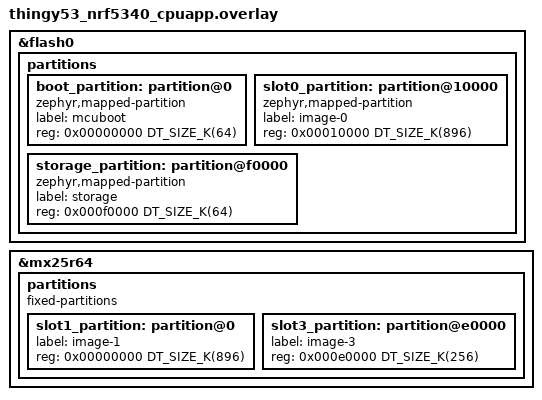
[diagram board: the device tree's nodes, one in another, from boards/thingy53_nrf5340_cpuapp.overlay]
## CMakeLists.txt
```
#
# Copyright (c) 2024 Nordic Semiconductor ASA
#
# SPDX-License-Identifier: LicenseRef-Nordic-5-Clause
#

cmake_minimum_required(VERSION 3.20.0)

find_package(Zephyr REQUIRED HINTS $ENV{ZEPHYR_BASE})
project(nrf_wifi_thread_coex)

target_sources(app PRIVATE
  src/ot_utils.c
  src/zperf_utils.c
  src/ot_coex_functions.c
  src/main.c
)

# For net_private.h
target_include_directories(app PUBLIC
  ${ZEPHYR_BASE}/subsys/net/ip
  ${ZEPHYR_BASE}/drivers/wifi/nrf_wifi/inc/
)
```

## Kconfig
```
#
# Copyright (c) 2024 Nordic Semiconductor
#
# SPDX-License-Identifier: LicenseRef-Nordic-5-Clause
#

source "Kconfig.zephyr"

menu "WiFi and Thread Coex sample"

config NET_CONFIG_PEER_IPV4_ADDR
	string "Peer IPv4 address"
	default "192.168.1.253"

config NET_CONFIG_PEER_IPV4_PORT
	int "Peer IPv4 port"
	default 5001

config WIFI_THREAD_STACK_SIZE
	int "Wi-Fi thread stack size"
	default 4096

config WIFI_THREAD_PRIORITY
	int "Wi-Fi thread priority"
	default 5

config WIFI_ZPERF_SERVER
	bool "Zperf role: server or client"

config WIFI_ZPERF_PROT_UDP
	bool "UDP or TCP"
	default y

config WIFI_ZPERF_PKT_SIZE
	int "packet size"
	default 1024

config WIFI_ZPERF_RATE
	int "rate in kbps"
	default 10000

# Thread configurations
config OT_CHANNEL
	int "Thread device operating channel"
	default 18

config OT_PAN_ID
	int "Thread device PAN ID"
	default 1

config OT_ROLE_CLIENT
	bool "Thread device role"
	default y

config OT_PACKET_SIZE
	int "Thread device packet size"
	default 256

config OT_RATE_BPS
	int "Thread device rate in bits per seconds"
	default 10000

config NET_CONFIG_THREAD_PORT
	int "Port for Thread zperf"
	default 5001

config OT_ZPERF_PROT_UDP
	bool "UDP or TCP"
	default y

# Test parameters
choice TEST_TYPE
	prompt "Test type"
	default TEST_TYPE_WLAN_OT

config TEST_TYPE_WLAN_ONLY
	bool "WLAN only"
	help
	  Enable WLAN only

config TEST_TYPE_OT_ONLY
	bool "Thread only"
	help
	  Enable Thread only

config TEST_TYPE_WLAN_OT
	bool "WLAN and Thread"
	help
	  Enable WLAN and Thread
endchoice

config TEST_TYPE_WLAN
	bool "WLAN"
	default y if TEST_TYPE_WLAN_ONLY || TEST_TYPE_WLAN_OT
	select WIFI
	help
	  Enable WLAN

config TEST_TYPE_OT
	bool "Thread"
	default y if TEST_TYPE_OT_ONLY || TEST_TYPE_WLAN_OT
	help
	  Enable Thread

config COEX_TEST_DURATION
	int "test duration in milliseconds"
	default 20000

config COEX_SEP_ANTENNAS
	bool "No support for shared antenna in Thread and WLAN. Set it to yes"
	default y

config SR_PROTOCOL_BLE
	bool "Indicates if the SR protocol is Bluetooth LE or not"

endmenu
```

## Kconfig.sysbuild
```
#
# Copyright (c) 2024 Nordic Semiconductor
#
# SPDX-License-Identifier: LicenseRef-Nordic-5-Clause
#

source "share/sysbuild/Kconfig"

config NRF_DEFAULT_IPC_RADIO
	depends on SOC_SERIES_NRF53 || SOC_SERIES_NRF54H
	default y
```

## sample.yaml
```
sample:
  description: Wi-Fi Thread coex sample application
  name: Wi-Fi Thread coex
tests:
  sample.nrf7002.thread_coex_sep_ant:
    sysbuild: true
    build_only: true
    integration_platforms:
      - nrf7002dk/nrf5340/cpuapp
    extra_args:
      - CONFIG_MPSL_CX=y
      - ipc_radio_CONFIG_MPSL_CX=y
      - CONFIG_COEX_SEP_ANTENNAS=y
      - EXTRA_CONF_FILE="overlay-wifi-udp-client-thread-udp-client.conf"
    platform_allow: nrf7002dk/nrf5340/cpuapp
    tags:
      - ci_build
      - sysbuild
      - ci_samples_wifi
  sample.nrf7001.thread_coex:
    sysbuild: true
    build_only: true
    integration_platforms:
      - nrf7002dk/nrf5340/cpuapp/nrf7001
    extra_args:
      - CONFIG_MPSL_CX=y
      - ipc_radio_CONFIG_MPSL_CX=y
      - CONFIG_COEX_SEP_ANTENNAS=y
      - EXTRA_CONF_FILE="overlay-wifi-udp-client-thread-udp-client.conf"
    platform_allow: nrf7002dk/nrf5340/cpuapp/nrf7001
    tags:
      - ci_build
      - sysbuild
      - ci_samples_wifi
  sample.nrf7002ek.thread_coex:
    sysbuild: true
    build_only: true
    integration_platforms:
      - nrf5340dk/nrf5340/cpuapp
    extra_args:
      - thread_coex_SHIELD="nrf7002ek;nrf7002ek_coex"
      - ipc_radio_SHIELD="nrf7002ek_coex"
      - CONFIG_MPSL_CX=y
      - ipc_radio_CONFIG_MPSL_CX=y
      - CONFIG_COEX_SEP_ANTENNAS=y
      - EXTRA_CONF_FILE="overlay-wifi-udp-client-thread-udp-client.conf"
    platform_allow: nrf5340dk/nrf5340/cpuapp
    tags:
      - ci_build
      - sysbuild
      - ci_samples_wifi
  sample.nrf7001ek.thread_coex:
    sysbuild: true
    build_only: true
    integration_platforms:
      - nrf5340dk/nrf5340/cpuapp
    extra_args:
      - thread_coex_SHIELD="nrf7002ek_nrf7001;nrf7002ek_coex"
      - ipc_radio_SHIELD="nrf7002ek_coex"
      - CONFIG_MPSL_CX=y
      - ipc_radio_CONFIG_MPSL_CX=y
      - CONFIG_COEX_SEP_ANTENNAS=y
      - EXTRA_CONF_FILE="overlay-wifi-udp-client-thread-udp-client.conf"
    platform_allow: nrf5340dk/nrf5340/cpuapp
    tags:
      - ci_build
      - sysbuild
      - ci_samples_wifi
  sample.nrf7002_eb.thingy53.thread_coex:
    sysbuild: true
    build_only: true
    extra_args:
      - thread_coex_SHIELD=nrf7002eb
      - ipc_radio_SHIELD=nrf7002eb_coex
      - CONFIG_MPSL_CX=y
      - ipc_radio_CONFIG_MPSL_CX=y
      - CONFIG_COEX_SEP_ANTENNAS=y
      - EXTRA_CONF_FILE="overlay-wifi-udp-client-thread-udp-client.conf"
    integration_platforms:
      - thingy53/nrf5340/cpuapp
    platform_allow: thingy53/nrf5340/cpuapp
    tags:
      - ci_build
      - sysbuild
      - ci_samples_wifi
  sample.54lm20dk.nrf7002eb2.thread_coex:
    sysbuild: true
    build_only: true
    extra_args:
      - SHIELD="nrf7002eb2;nrf7002eb2_coex"
      - CONFIG_MPSL_CX=y
      - CONFIG_COEX_SEP_ANTENNAS=y
      - EXTRA_CONF_FILE="overlay-wifi-udp-client-thread-udp-client.conf"
    integration_platforms:
      - nrf54lm20dk/nrf54lm20a/cpuapp
    platform_allow:
      - nrf54lm20dk/nrf54lm20a/cpuapp
    tags:
      - ci_build
      - sysbuild
      - ci_samples_wifi
```

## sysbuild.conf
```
#
# Copyright (c) 2024 Nordic Semiconductor ASA
#
# SPDX-License-Identifier: LicenseRef-Nordic-5-Clause
#

SB_CONFIG_WIFI_NRF700X=y
```

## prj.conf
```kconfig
#
# Copyright (c) 2024 Nordic Semiconductor ASA
#
# SPDX-License-Identifier: LicenseRef-Nordic-5-Clause
#
CONFIG_WIFI=y

# WPA supplicant
CONFIG_WIFI_NM_WPA_SUPPLICANT=y

# Networking
CONFIG_NETWORKING=y
CONFIG_NET_SOCKETS=y
CONFIG_NET_LOG=y
CONFIG_NET_IPV4=y
CONFIG_NET_UDP=y
CONFIG_NET_TCP=y
CONFIG_NET_DHCPV4=y

CONFIG_NET_IF_UNICAST_IPV4_ADDR_COUNT=2
CONFIG_NET_MAX_CONTEXTS=8
CONFIG_NET_CONTEXT_SYNC_RECV=y

CONFIG_INIT_STACKS=y

CONFIG_NET_L2_ETHERNET=y

CONFIG_NET_CONFIG_SETTINGS=y
CONFIG_NET_CONFIG_INIT_TIMEOUT=0

# Memories
CONFIG_MAIN_STACK_SIZE=5200
CONFIG_NET_TX_STACK_SIZE=4096
CONFIG_NET_RX_STACK_SIZE=4096

# Debugging
CONFIG_STACK_SENTINEL=y
CONFIG_DEBUG_COREDUMP=y
CONFIG_DEBUG_COREDUMP_BACKEND_LOGGING=y
CONFIG_DEBUG_COREDUMP_MEMORY_DUMP_MIN=y

# Kernel options
CONFIG_ENTROPY_GENERATOR=y

# Logging
CONFIG_LOG=y
CONFIG_PRINTK=y
CONFIG_POSIX_TIMERS=y

# Benchmarking
CONFIG_NET_ZPERF=y

# Optimized networking settings for performance
CONFIG_NET_TC_TX_COUNT=1
CONFIG_HEAP_MEM_POOL_SIZE=41808
CONFIG_NRF_WIFI_CTRL_HEAP_SIZE=20000
CONFIG_NRF_WIFI_DATA_HEAP_SIZE=168192


# Below Wi-Fi configs need to be modified based on security
CONFIG_WIFI_CREDENTIALS=y
CONFIG_WIFI_CREDENTIALS_STATIC=y
CONFIG_WIFI_CREDENTIALS_STATIC_SSID="Myssid"
CONFIG_WIFI_CREDENTIALS_STATIC_PASSWORD="Mypassword"

CONFIG_NET_CONFIG_MY_IPV4_ADDR="192.168.1.99"
CONFIG_NET_CONFIG_MY_IPV4_NETMASK="255.255.255.0"
CONFIG_NET_CONFIG_MY_IPV4_GW="192.168.1.1"

# DUT Wi-Fi zperf configuration
CONFIG_WIFI_ZPERF_PKT_SIZE=1024
CONFIG_WIFI_ZPERF_RATE=10000

CONFIG_NRF_WIFI_LOW_POWER=y

CONFIG_LOG_BUFFER_SIZE=2048
CONFIG_NET_MGMT_EVENT_QUEUE_TIMEOUT=5000

# Thread configurations
CONFIG_OT_CHANNEL=22
CONFIG_OT_PAN_ID=1
CONFIG_OT_PACKET_SIZE=256
CONFIG_OT_RATE_BPS=65000

CONFIG_NET_ZPERF=y
CONFIG_NET_LOG=y

# To handle multiple interfaces.
CONFIG_NET_CONFIG_SETTINGS=y
CONFIG_NET_CONFIG_INIT_TIMEOUT=0
CONFIG_NET_CONFIG_AUTO_INIT=n

# test duration in milliseconds
CONFIG_COEX_TEST_DURATION=30000

CONFIG_ZVFS_POLL_MAX=10
CONFIG_MBEDTLS_MD_C=y

CONFIG_NET_L2_OPENTHREAD=y
CONFIG_OPENTHREAD_NORDIC_LIBRARY_MASTER=y
CONFIG_NET_IF_MAX_IPV6_COUNT=2
CONFIG_NET_IF_MAX_IPV4_COUNT=2
CONFIG_NET_MGMT_EVENT_QUEUE_SIZE=8
# Required by WIFI
CONFIG_PSA_WANT_ALG_SHA_1=y

# Optimized networking settings for performance
CONFIG_NET_PKT_RX_COUNT=2
CONFIG_NET_PKT_TX_COUNT=8
CONFIG_NET_BUF_RX_COUNT=2
CONFIG_NET_BUF_TX_COUNT=16

# Wi-Fi zperf configuration
CONFIG_WIFI_ZPERF_PROT_UDP=y
CONFIG_NET_ZPERF_SERVER=y

# Thread zperf configuration
CONFIG_OT_ZPERF_PROT_UDP=y
CONFIG_OT_ROLE_CLIENT=y

# control log level
CONFIG_OPENTHREAD_L2_LOG_LEVEL_OFF=y
CONFIG_IEEE802154_DRIVER_LOG_LEVEL_OFF=y
CONFIG_NET_PKT_LOG_LEVEL_OFF=y

# Joiner + PSA crypto on the OpenThread workqueue overflows the default
# stack size when Wi-Fi and Thread coexistence (MPSL_CX) are active.
CONFIG_OPENTHREAD_THREAD_STACK_SIZE=10240
```

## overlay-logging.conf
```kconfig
#
# Copyright (c) 2024 Nordic Semiconductor ASA
#
# SPDX-License-Identifier: LicenseRef-Nordic-5-Clause
#
# Enable Zephyr logging
CONFIG_LOG=y

# Increase the default RX stack size
CONFIG_IEEE802154_NRF5_RX_STACK_SIZE=832

# Use separate thread for logging
CONFIG_LOG_MODE_DEFERRED=y

# Increase max log level to informative
CONFIG_LOG_MAX_LEVEL=3

# Option for configuring log level in this sample
#CONFIG_OT_COMMAND_LINE_INTERFACE_LOG_LEVEL_INF=y

# Enable net module logging
# CONFIG_NET_LOG=y
# Option for configuring log level in net config library
# CONFIG_NET_CONFIG_LOG_LEVEL_INF=y

# Option for configuring log level in Zephyr L2 logging
# CONFIG_OPENTHREAD_L2_DEBUG=y
# CONFIG_OPENTHREAD_L2_LOG_LEVEL_DBG=y
# CONFIG_OPENTHREAD_L2_DEBUG_DUMP_15_4=y
# CONFIG_OPENTHREAD_L2_DEBUG_DUMP_IPV6=y

# Enable Mbed TLS logging
#CONFIG_OPENTHREAD_MBEDTLS_DEBUG=y
#CONFIG_MBEDTLS_DEBUG_LEVEL=3

# Enable OpenThread logging
CONFIG_OPENTHREAD_DEBUG=y
# Option for configuring log level in OpenThread
CONFIG_OPENTHREAD_LOG_LEVEL_INFO=y

# Enable RTT logging backend
CONFIG_USE_SEGGER_RTT=y
CONFIG_LOG_BACKEND_RTT=y

# Disable UART logging backend
# CONFIG_LOG_BACKEND_UART=n
CONFIG_SHELL_LOG_BACKEND=n
# Testing Twister test scope with flag CI-all-test
```

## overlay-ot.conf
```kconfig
#
# Copyright (c) 2024 Nordic Semiconductor ASA
#
# SPDX-License-Identifier: LicenseRef-Nordic-5-Clause
#
CONFIG_NETWORKING=y
CONFIG_NET_L2_OPENTHREAD=y
CONFIG_OPENTHREAD_NORDIC_LIBRARY_MASTER=y
CONFIG_NET_IF_MAX_IPV6_COUNT=2
CONFIG_NET_IF_MAX_IPV4_COUNT=2
CONFIG_NET_MGMT_EVENT_QUEUE_SIZE=8
# Required by WIFI
CONFIG_MBEDTLS_SHA1_C=y
```

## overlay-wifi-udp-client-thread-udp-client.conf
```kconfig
#
# Copyright (c) 2024 Nordic Semiconductor ASA
#
# SPDX-License-Identifier: LicenseRef-Nordic-5-Clause
#
# Optimized networking settings for performance
CONFIG_NET_PKT_RX_COUNT=2
CONFIG_NET_PKT_TX_COUNT=8
CONFIG_NET_BUF_RX_COUNT=2
CONFIG_NET_BUF_TX_COUNT=16
# Thread zperf configuration
CONFIG_OT_ROLE_CLIENT=y
```

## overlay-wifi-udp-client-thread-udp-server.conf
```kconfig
#
# Copyright (c) 2024 Nordic Semiconductor ASA
#
# SPDX-License-Identifier: LicenseRef-Nordic-5-Clause
#
# Optimized networking settings for performance
CONFIG_NET_PKT_RX_COUNT=12
CONFIG_NET_PKT_TX_COUNT=4
CONFIG_NET_BUF_RX_COUNT=12
CONFIG_NET_BUF_TX_COUNT=8
# Thread zperf configuration
CONFIG_OT_ROLE_CLIENT=n
```

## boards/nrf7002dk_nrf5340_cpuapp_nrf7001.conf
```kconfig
#
# Copyright (c) 2026 Nordic Semiconductor ASA
#
# SPDX-License-Identifier: LicenseRef-Nordic-5-Clause
#

#NRF70 specific configuration
CONFIG_WIFI_NRF70=y
CONFIG_NRF70_SR_COEX=y
CONFIG_NRF70_SR_COEX_RF_SWITCH=y
CONFIG_NRF70_RX_NUM_BUFS=48
CONFIG_NRF70_MAX_TX_AGGREGATION=12
CONFIG_NRF70_MAX_TX_PENDING_QLEN=12
CONFIG_NRF70_QSPI_LOW_POWER=n
```

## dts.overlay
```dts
&uart0 {
	/* Disabling hardware flow control to free up pins for other purposes. */
     /delete-property/ hw-flow-control;
};
```

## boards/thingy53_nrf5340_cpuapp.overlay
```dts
/*
 * Copyright (c) 2024 Nordic Semiconductor ASA
 *
 * SPDX-License-Identifier: LicenseRef-Nordic-5-Clause
 */

/delete-node/ &boot_partition;
/delete-node/ &slot0_partition;
/delete-node/ &slot1_partition;
/delete-node/ &storage_partition;

&flash0 {
	partitions {
		ranges;
		#address-cells = <1>;
		#size-cells = <1>;

		boot_partition: partition@0 {
			compatible = "zephyr,mapped-partition";
			label = "mcuboot";
			reg = <0x00000000 DT_SIZE_K(64)>;
		};

		slot0_partition: partition@10000 {
			compatible = "zephyr,mapped-partition";
			label = "image-0";
			reg = <0x00010000 DT_SIZE_K(896)>;
		};

		storage_partition: partition@f0000 {
			compatible = "zephyr,mapped-partition";
			label = "storage";
			reg = <0x000f0000 DT_SIZE_K(64)>;
		};
	};
};

&mx25r64 {
	status = "okay";

	partitions {
		compatible = "fixed-partitions";
		#address-cells = <1>;
		#size-cells = <1>;

		slot1_partition: partition@0 {
			label = "image-1";
			reg = <0x00000000 DT_SIZE_K(896)>;
		};

		slot3_partition: partition@e0000 {
			label = "image-3";
			reg = <0x000e0000 DT_SIZE_K(256)>;
		};
	};
};
```

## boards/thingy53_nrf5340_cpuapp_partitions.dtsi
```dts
/*
 * Copyright (c) 2024 Nordic Semiconductor ASA
 *
 * SPDX-License-Identifier: LicenseRef-Nordic-5-Clause
 */

/*
 * Shared flash partition layout for thingy53/nrf5340/cpuapp.
 *
 * Internal flash (flash0, 1 MB):
 *   boot_partition    @ 0x000000  64 KB  MCUboot
 *   slot0_partition   @ 0x010000 896 KB  Image 0 primary (app)
 *   storage_partition @ 0x0f0000  64 KB  Settings
 *
 * External QSPI flash (mx25r64):
 *   slot1_partition   @ 0x000000 896 KB  Image 0 secondary (OTA)
 *   slot3_partition   @ 0x0e0000 256 KB  Image 1 secondary (network core OTA)
 */

/delete-node/ &boot_partition;
/delete-node/ &slot0_partition;
/delete-node/ &slot1_partition;
/delete-node/ &storage_partition;

&flash0 {
	partitions {
		ranges;
		#address-cells = <1>;
		#size-cells = <1>;

		boot_partition: partition@0 {
			compatible = "zephyr,mapped-partition";
			label = "mcuboot";
			reg = <0x00000000 DT_SIZE_K(64)>;
		};

		slot0_partition: partition@10000 {
			compatible = "zephyr,mapped-partition";
			label = "image-0";
			reg = <0x00010000 DT_SIZE_K(896)>;
		};

		storage_partition: partition@f0000 {
			compatible = "zephyr,mapped-partition";
			label = "storage";
			reg = <0x000f0000 DT_SIZE_K(64)>;
		};
	};
};

&mx25r64 {
	status = "okay";

	partitions {
		compatible = "fixed-partitions";
		#address-cells = <1>;
		#size-cells = <1>;

		slot1_partition: partition@0 {
			label = "image-1";
			reg = <0x00000000 DT_SIZE_K(896)>;
		};

		slot3_partition: partition@e0000 {
			label = "image-3";
			reg = <0x000e0000 DT_SIZE_K(256)>;
		};
	};
};
```

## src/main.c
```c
/**
 * Copyright (c) 2024 Nordic Semiconductor ASA
 *
 * SPDX-License-Identifier: LicenseRef-Nordic-5-Clause
 */

#include "main.h"

int setup_interfaces(void)
{
	const struct device *dev = device_get_binding("wlan0");
	/* Without this, DHCPv4 starts on first interface and if that is not Wi-Fi or
	 * only supports IPv6, then its an issue. (E.g., OpenThread)
	 *
	 * So, DHCPv4 is started on Wi-Fi interface always, independent of the ordering.
	 */
	struct net_if *wifi_iface = net_if_lookup_by_dev(dev);

	/* As both are Ethernet, need to set specific interface */
	net_if_set_default(wifi_iface);

	net_config_init_app(dev, "Initializing network");

	return 0;
}

int main(void)
{
	int ret = 0;
	bool is_ant_mode_sep = IS_ENABLED(CONFIG_COEX_SEP_ANTENNAS);
	bool is_ot_client = IS_ENABLED(CONFIG_OT_ROLE_CLIENT);
	bool is_wifi_server = IS_ENABLED(CONFIG_WIFI_ZPERF_SERVER);
	bool is_wifi_zperf_udp = IS_ENABLED(CONFIG_WIFI_ZPERF_PROT_UDP);
	bool is_ot_zperf_udp = IS_ENABLED(CONFIG_OT_ZPERF_PROT_UDP);
	bool test_wifi = IS_ENABLED(CONFIG_TEST_TYPE_WLAN);
	bool test_thread = IS_ENABLED(CONFIG_TEST_TYPE_OT);
	bool is_sr_protocol_ble = IS_ENABLED(CONFIG_SR_PROTOCOL_BLE);

	/* LOG_INF("Set up interfaces"); */
	ret = setup_interfaces();
	if (ret) {
		LOG_INF("Failed to setup ifaces: %d\n", ret);
		return -1;
	}

#if !defined(CONFIG_COEX_SEP_ANTENNAS) && !(CONFIG_NRF70_SR_COEX_RF_SWITCH)
	BUILD_ASSERT("Shared antenna support is not available with nRF7002 shields");
#endif

	/* register callback functions */
	wifi_init();

#ifdef CONFIG_NRF70_SR_COEX_RF_SWITCH
	/* Configure SR side (nRF5340 side) switch in nRF700x */
	/* LOG_INF("Configure SR side switch"); */
	ret = nrf_wifi_config_sr_switch(is_ant_mode_sep);
	if (ret != 0) {
		LOG_ERR("Unable to configure SR side switch: %d", ret);
		return ret;
	}
#endif /* CONFIG_NRF70_SR_COEX_RF_SWITCH */

#if defined(CONFIG_NRF70_SR_COEX)
	/* Configure non-PTA registers of Coexistence Hardware */
	/* LOG_INF("Configuring non-PTA registers."); */
	ret = nrf_wifi_coex_config_non_pta(is_ant_mode_sep, is_sr_protocol_ble);
	if (ret != 0) {
		LOG_ERR("Configuring non-PTA registers of CoexHardware FAIL");
		return ret;
	}
#endif /* CONFIG_NRF70_SR_COEX */

	ret = wifi_tput_ot_tput(test_wifi, is_ant_mode_sep,
		test_thread, is_ot_client, is_wifi_server, is_wifi_zperf_udp, is_ot_zperf_udp,
		is_sr_protocol_ble);

	if (ret != 0) {
		LOG_INF("Test case failed. Returning with error");
		return ret;
	}

	/* Disable coexistence hardware */
	nrf_wifi_coex_hw_reset();

	LOG_INF("\nCoexistence test complete\n");

	return 0;
}
```

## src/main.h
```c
/*
 * Copyright (c) 2024 Nordic Semiconductor ASA
 *
 * SPDX-License-Identifier: LicenseRef-Nordic-5-Clause
 */

#ifndef MAIN_H_
#define MAIN_H_

#include <stdio.h>
#include <stdlib.h>
#include <string.h>
#include <stdbool.h>

#include <zephyr/logging/log.h>
LOG_MODULE_REGISTER(main, CONFIG_LOG_DEFAULT_LEVEL);

#include <zephyr/kernel.h>
#include <zephyr/init.h>
#include <zephyr/device.h>
#include <zephyr/devicetree.h>
#include <zephyr/drivers/gpio.h>
#include <zephyr/shell/shell.h>
#include <zephyr/shell/shell_uart.h>
#include <zephyr/sys/byteorder.h>
#include <zephyr/net/zperf.h>
#include <zephyr/net/net_if.h>
#include <zephyr/net/wifi_mgmt.h>
#include <zephyr/net/net_event.h>
#include <zephyr/net/socket.h>

#include "coex.h"


/**
 * @brief Function to test Wi-Fi throughput client/server and Thread throughput client/server
 *
 * @return Zero on success or (negative) error code otherwise.
 */
int wifi_tput_ot_tput(bool test_wifi, bool is_ant_mode_sep, bool test_thread,
		bool is_ot_client, bool is_wifi_server, bool is_wifi_zperf_udp,
		bool is_ot_zperf_udp, bool is_sr_protocol_ble);

/**
 * @brief memset_context
 *
 * @return No return value.
 */
void memset_context(void);

/**
 * @brief Handle net management callbacks
 *
 * @return No return value.
 */
void wifi_mgmt_callback_functions(void);

/**
 * @brief Wi-Fi init.
 *
 * @return None
 */
void wifi_init(void);

/**
 * @brief Network configuration
 *
 * @return status
 */
int net_config_init_app(const struct device *dev, const char *app_info);

#endif /* MAIN_H_ */
```

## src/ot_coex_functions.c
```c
/**
 * Copyright (c) 2024 Nordic Semiconductor ASA
 *
 * SPDX-License-Identifier: LicenseRef-Nordic-5-Clause
 */

#include "ot_coex_functions.h"

#if defined(CONFIG_NRFX_CLOCK_HFCLK) && defined(CLOCK_FEATURE_HFCLK_DIVIDE_PRESENT)
#include <zephyr/drivers/clock_control/nrf_clock_control.h>

#define HFCLK_REQUESTED_FREQUENCY MHZ(128)
#endif

bool is_ot_device_role_client;

uint8_t ot_wait4_ping_reply_from_peer;

/* Wi-Fi utils */
int cmd_wifi_status(void)
{
	struct net_if *iface = net_if_get_first_wifi();

	if (net_mgmt(NET_REQUEST_WIFI_IFACE_STATUS, iface, &wifi_if_status,
				sizeof(struct wifi_iface_status))) {
		LOG_INF("Status request failed");

		return -ENOEXEC;
	}

	if (wifi_if_status.state < WIFI_STATE_ASSOCIATED) {
		return 0; /* Exit early if not associated */
	}

	uint8_t mac_string_buf[sizeof("xx:xx:xx:xx:xx:xx")];

	if (print_wifi_conn_status_once == 1) {
		LOG_INF("Interface Mode: %s", wifi_mode_txt(wifi_if_status.iface_mode));
		LOG_INF("Link Mode: %s", wifi_link_mode_txt(wifi_if_status.link_mode));
		LOG_INF("SSID: %-32s", wifi_if_status.ssid);
		LOG_INF("BSSID: %s",
				net_sprint_ll_addr_buf(wifi_if_status.bssid, WIFI_MAC_ADDR_LEN,
					mac_string_buf, sizeof(mac_string_buf)));
		LOG_INF("Band: %s", wifi_band_txt(wifi_if_status.band));
		LOG_INF("Channel: %d", wifi_if_status.channel);
		LOG_INF("Security: %s", wifi_security_txt(wifi_if_status.security));
		/* LOG_INF("MFP: %s", wifi_mfp_txt(wifi_if_status.mfp)); */
		LOG_INF("Wi-Fi RSSI: %d", wifi_if_status.rssi);

		print_wifi_conn_status_once++;
	}

	return 0;
}

void memset_context(void)
{
	memset(&wifi_context, 0, sizeof(wifi_context));
}

void wifi_mgmt_callback_functions(void)
{
	net_mgmt_init_event_callback(&wifi_sta_mgmt_cb, wifi_mgmt_event_handler,
		WIFI_MGMT_EVENTS);

	net_mgmt_add_event_callback(&wifi_sta_mgmt_cb);

	net_mgmt_init_event_callback(&net_addr_mgmt_cb, net_mgmt_event_handler,
		NET_EVENT_IPV4_DHCP_BOUND);

	net_mgmt_add_event_callback(&net_addr_mgmt_cb);

#if defined(CONFIG_NRFX_CLOCK_HFCLK) && defined(CLOCK_FEATURE_HFCLK_DIVIDE_PRESENT)
	clock_control_set_rate(DEVICE_DT_GET_ONE(nordic_nrf_clock_hfclk), NULL,
			       (clock_control_subsys_rate_t)HFCLK_REQUESTED_FREQUENCY);
#endif

	LOG_INF("Starting %s with CPU frequency: %d MHz", CONFIG_BOARD, SystemCoreClock/MHZ(1));

	k_sleep(K_SECONDS(1));
}

void wifi_init(void)
{
	memset_context();
	wifi_mgmt_callback_functions();
}

void net_mgmt_event_handler(struct net_mgmt_event_callback *cb, uint64_t mgmt_event,
		struct net_if *iface)
{
	switch (mgmt_event) {
	case NET_EVENT_IPV4_DHCP_BOUND:
		print_dhcp_ip(cb);
		break;
	default:
		break;
	}
}

void wifi_mgmt_event_handler(struct net_mgmt_event_callback *cb,
		uint64_t mgmt_event, struct net_if *iface)
{
	const struct device *dev = iface->if_dev->dev;
	struct nrf_wifi_vif_ctx_zep *vif_ctx_zep = NULL;

	vif_ctx_zep = dev->data;

	switch (mgmt_event) {
	case NET_EVENT_WIFI_CONNECT_RESULT:
		handle_wifi_connect_result(cb);
		break;
	case NET_EVENT_WIFI_DISCONNECT_RESULT:
		handle_wifi_disconnect_result(cb);
		break;
	default:
		break;
	}
}

void handle_wifi_connect_result(struct net_mgmt_event_callback *cb)
{
	const struct wifi_status *status =
		(const struct wifi_status *) cb->info;

	if (status->status) {
		LOG_ERR("Wi-Fi Connection request failed (%d)", status->status);
	} else {
		LOG_INF("Connected");
		wifi_context.connected = true;
	}

	cmd_wifi_status();

	k_sem_give(&wait_for_next);
}

void handle_wifi_disconnect_result(struct net_mgmt_event_callback *cb)
{
	if (wifi_context.disconnect_requested) {
		wifi_context.disconnect_requested = false;
	} else {
		wifi_context.connected = false;
	}
	cmd_wifi_status();
}


void print_dhcp_ip(struct net_mgmt_event_callback *cb)
{
	/* Get DHCP info from struct net_if_dhcpv4 and print */
	const struct net_if_dhcpv4 *dhcpv4 = cb->info;
	const struct in_addr *addr = &dhcpv4->requested_ip;
	char dhcp_info[128];

	net_addr_ntop(AF_INET, addr, dhcp_info, sizeof(dhcp_info));

	LOG_INF("IP address: %s", dhcp_info);
	k_sem_give(&wait_for_next);
}

int cmd_wifi_scan(void)
{
	struct net_if *iface = net_if_get_first_wifi();
	struct wifi_scan_params params = {0};

	if (net_mgmt(NET_REQUEST_WIFI_SCAN, iface, &params, sizeof(struct wifi_scan_params))) {
		LOG_ERR("Scan request failed");
		return -ENOEXEC;
	}
	LOG_INF("Scan requested");
	return 0;
}

int wifi_connect(void)
{
	struct net_if *iface = net_if_get_first_wifi();

	if (net_mgmt(NET_REQUEST_WIFI_CONNECT_STORED, iface, NULL, 0)) {
		LOG_ERR("Connection request failed");

		return -ENOEXEC;
	}

	LOG_INF("Connection requested");

	return 0;
}

int wifi_disconnect(void)
{
	struct net_if *iface = net_if_get_first_wifi();
	int wifi_if_status;

	wifi_context.disconnect_requested = true;

	wifi_if_status = net_mgmt(NET_REQUEST_WIFI_DISCONNECT, iface, NULL, 0);

	if (wifi_if_status) {
		wifi_context.disconnect_requested = false;

		if (wifi_if_status == -EALREADY) {
			LOG_ERR("Already disconnected");
		} else {
			LOG_ERR("Disconnect request failed");
			return -ENOEXEC;
		}
	}
	return 0;
}

int parse_ipv4_addr(char *host, struct sockaddr_in *addr)
{
	int ret;

	if (!host) {
		return -EINVAL;
	}
	ret = net_addr_pton(AF_INET, host, &addr->sin_addr);
	if (ret < 0) {
		LOG_ERR("Invalid IPv4 address %s", host);
		return -EINVAL;
	}
	LOG_INF("Wi-Fi peer IPv4 address %s", host);

	return 0;
}

int wifi_connection(void)
{
	/* Wi-Fi connection */
	wifi_connect();

	if (wifi_wait_for_next_event("Wi-Fi Connection", WIFI_CONNECTION_TIMEOUT_SEC)) {
		LOG_INF("Wi-Fi Connection timeout");
		return -1;
	}

	if (wifi_wait_for_next_event("Wi-Fi DHCP", WIFI_DHCP_TIMEOUT_SEC)) {
		LOG_INF("Wi-Fi DHCP timeout");
		return -1;
	}

	return 0;
}

void wifi_disconnection(void)
{
	int ret = 0;

	/* Wi-Fi disconnection */
	LOG_INF("Disconnecting Wi-Fi");
	ret = wifi_disconnect();
	if (ret != 0) {
		LOG_INF("Wi-Fi Disconnect failed");
	}
}

/* coexistence functions */
int wifi_wait_for_next_event(const char *event_name, int timeout)
{
	int wait_result;

	if (event_name) {
		LOG_INF("Waiting for %s", event_name);
	}
	wait_result = k_sem_take(&wait_for_next, K_SECONDS(timeout));
	if (wait_result) {
		LOG_ERR("Timeout waiting for %s -> %d", event_name, wait_result);
		return -1;
	}
	LOG_INF("Got %s", event_name);
	k_sem_reset(&wait_for_next);

	return 0;
}

void tcp_upload_results_cb(enum zperf_status status, struct zperf_results *result,
		void *user_data)
{
	uint32_t client_rate_in_kbps;

	switch (status) {
	case ZPERF_SESSION_STARTED:
		LOG_INF("Wi-Fi: New TCP session started.\n");
		wait4_peer_wifi_client_to_start_tput = 1;
		break;
	case ZPERF_SESSION_PERIODIC_RESULT:
		/* Ignored. */
		break;
	case ZPERF_SESSION_FINISHED: {

		if (result->client_time_in_us != 0U) {
			client_rate_in_kbps = (uint32_t)
				(((uint64_t)result->nb_packets_sent *
				  (uint64_t)result->packet_size * (uint64_t)8 *
				  (uint64_t)USEC_PER_SEC) /
				 ((uint64_t)result->client_time_in_us * 1024U));
		} else {
			client_rate_in_kbps = 0U;
		}

		LOG_INF("Duration:\t%llu", result->client_time_in_us);
		LOG_INF("Num packets:\t%u", result->nb_packets_sent);
		LOG_INF("Num errors:\t%u (retry or fail)\n",
						result->nb_packets_errors);
		LOG_INF("\nclient data rate = %u kbps", client_rate_in_kbps);
		k_sem_give(&udp_tcp_callback);
		break;
	}

	case ZPERF_SESSION_ERROR:
		LOG_INF("Wi-Fi: TCP upload failed\n");
		break;
	}
}

void tcp_download_results_cb(enum zperf_status status, struct zperf_results *result,
		void *user_data)
{
	uint32_t rate_in_kbps;

	switch (status) {
	case ZPERF_SESSION_STARTED:
		LOG_INF("Wi-Fi: New TCP session started.\n");
		wait4_peer_wifi_client_to_start_tput = 1;
		break;
	case ZPERF_SESSION_PERIODIC_RESULT:
		/* Ignored. */
		break;
	case ZPERF_SESSION_FINISHED: {
		/* Compute baud rate */
		if (result->time_in_us != 0U) {
			rate_in_kbps = (uint32_t)
				(((uint64_t)result->total_len * 8ULL *
				  (uint64_t)USEC_PER_SEC) /
				 ((uint64_t)result->time_in_us * 1024ULL));
		} else {
			rate_in_kbps = 0U;
		}

		LOG_INF("Wi-Fi: TCP session ended\n");
		/** LOG_INF("%u bytes in %u ms:", result->total_len,
		 *			result->time_in_us/USEC_PER_MSEC);
		 */
		LOG_INF("\nThroughput:%u kbps", rate_in_kbps);
		LOG_INF("");
		k_sem_give(&udp_tcp_callback);
		break;
	}

	case ZPERF_SESSION_ERROR:
		LOG_INF("TCP session error.\n");
		break;
	}
}

void udp_download_results_cb(enum zperf_status status, struct zperf_results *result,
		void *user_data)
{
	switch (status) {
	case ZPERF_SESSION_STARTED:
		LOG_INF("Wi-Fi: new UDP session started.");
		wait4_peer_wifi_client_to_start_tput = 1;
		break;
	case ZPERF_SESSION_PERIODIC_RESULT:
		/* Ignored. */
		break;
	case ZPERF_SESSION_FINISHED: {
		uint32_t rate_in_kbps;

		/* Compute baud rate */
		if (result->time_in_us != 0U) {
			rate_in_kbps = (uint32_t)
				(((uint64_t)result->total_len * 8ULL *
				  (uint64_t)USEC_PER_SEC) /
				 ((uint64_t)result->time_in_us * 1024ULL));
		} else {
			rate_in_kbps = 0U;
		}

		LOG_INF("Wi-Fi: UDP end of session!");

		LOG_INF("Wi-Fi: Download results:");
		LOG_INF("%u bytes in %llu ms",
				(result->nb_packets_rcvd * result->packet_size),
				(result->time_in_us / USEC_PER_MSEC));
		/**
		 *LOG_INF(" received packets:\t%u",
		 *		  result->nb_packets_rcvd);
		 *LOG_INF(" nb packets lost:\t%u",
		 *		  result->nb_packets_lost);
		 *LOG_INF(" nb packets outorder:\t%u",
		 *		  result->nb_packets_outorder);
		 */
		LOG_INF("\nThroughput:%u kbps", rate_in_kbps);
		LOG_INF("");
		k_sem_give(&udp_tcp_callback);
		break;
	}

	case ZPERF_SESSION_ERROR:
		LOG_INF("Wi-Fi: UDP session error.");
		break;
	}
}


void udp_upload_results_cb(enum zperf_status status, struct zperf_results *result,
		void *user_data)
{
	unsigned int client_rate_in_kbps;

	switch (status) {
	case ZPERF_SESSION_STARTED:
		LOG_INF("Wi-Fi: UDP upload session started");
		wait4_peer_wifi_client_to_start_tput = 1;
		break;
	case ZPERF_SESSION_PERIODIC_RESULT:
		/* Ignored. */
		break;
	case ZPERF_SESSION_FINISHED:
		LOG_INF("Wi-Fi benchmark: Upload completed!");
		if (result->client_time_in_us != 0U) {
			client_rate_in_kbps = (uint32_t)
				(((uint64_t)result->nb_packets_sent *
				  (uint64_t)result->packet_size * (uint64_t)8 *
				  (uint64_t)USEC_PER_SEC) /
				 ((uint64_t)result->client_time_in_us * 1024U));
		} else {
			client_rate_in_kbps = 0U;
		}
		k_sem_give(&udp_tcp_callback);
		break;
	case ZPERF_SESSION_ERROR:
		LOG_ERR("Wi-Fi: UDP upload session error");
		break;
	}
}
enum nrf_wifi_pta_wlan_op_band wifi_mgmt_to_pta_band(enum wifi_frequency_bands band)
{
	switch (band) {
	case WIFI_FREQ_BAND_2_4_GHZ:
		return NRF_WIFI_PTA_WLAN_OP_BAND_2_4_GHZ;
	case WIFI_FREQ_BAND_5_GHZ:
		return NRF_WIFI_PTA_WLAN_OP_BAND_5_GHZ;
	default:
		return NRF_WIFI_PTA_WLAN_OP_BAND_NONE;
	}
}

int run_wifi_traffic_tcp(bool is_wifi_server)
{
	int ret = 0;

	if (is_wifi_server) {
		struct zperf_download_params params = {0};

		params.port = CONFIG_NET_CONFIG_PEER_IPV4_PORT;

		ret = zperf_tcp_download(&params, tcp_download_results_cb, NULL);
		if (ret != 0) {
			LOG_ERR("Wi-Fi: Failed to start TCP server session: %d", ret);
			return ret;
		}
		LOG_INF("Wi-Fi: TCP server started on port %u\n", params.port);
	} else {
		struct zperf_upload_params params = {0};
		/* Start Wi-Fi TCP traffic */
		LOG_INF("Wi-Fi: Starting Wi-Fi benchmark: Zperf TCP client");
		params.duration_ms = CONFIG_COEX_TEST_DURATION;
		params.rate_kbps = CONFIG_WIFI_ZPERF_RATE;
		params.packet_size = CONFIG_WIFI_ZPERF_PKT_SIZE;
		parse_ipv4_addr(CONFIG_NET_CONFIG_PEER_IPV4_ADDR, &in4_addr_my);
		net_sprint_ipv4_addr(&in4_addr_my.sin_addr);

		memcpy(&params.peer_addr, &in4_addr_my, sizeof(in4_addr_my));

		ret = zperf_tcp_upload_async(&params, tcp_upload_results_cb, NULL);
		if (ret != 0) {
			LOG_ERR("Wi-Fi: Failed to start TCP session: %d", ret);
			return ret;
		}
	}

	return 0;
}

int run_wifi_traffic_udp(bool is_wifi_server)
{
	int ret = 0;

	if (is_wifi_server) {
		struct zperf_download_params params = {0};

		params.port = CONFIG_NET_CONFIG_PEER_IPV4_PORT;

		ret = zperf_udp_download(&params, udp_download_results_cb, NULL);
		if (ret != 0) {
			LOG_ERR("Wi-Fi: Failed to start UDP server session: %d", ret);
			return ret;
		}
	} else {
		struct zperf_upload_params params = {0};

		/* Start Wi-Fi UDP traffic */
		LOG_INF("Starting Wi-Fi benchmark: Zperf UDP client");
		params.duration_ms = CONFIG_COEX_TEST_DURATION;
		params.rate_kbps = CONFIG_WIFI_ZPERF_RATE;
		params.packet_size = CONFIG_WIFI_ZPERF_PKT_SIZE;

		parse_ipv4_addr(CONFIG_NET_CONFIG_PEER_IPV4_ADDR, &in4_addr_my);
		net_sprint_ipv4_addr(&in4_addr_my.sin_addr);

		memcpy(&params.peer_addr, &in4_addr_my, sizeof(in4_addr_my));
		ret = zperf_udp_upload_async(&params, udp_upload_results_cb, NULL);
		if (ret != 0) {
			LOG_ERR("Failed to start Wi-Fi UDP benchmark: %d", ret);
			return ret;
		}
	}
	return 0;
}

void check_wifi_traffic(void)
{
	/* Run Wi-Fi traffic */
	if (k_sem_take(&udp_tcp_callback, K_FOREVER) != 0) {
		LOG_ERR("Wi-Fi: Results are not ready");
	} else {
#ifdef CONFIG_WIFI_ZPERF_PROT_UDP
		LOG_INF("Wi-Fi UDP session finished");
#else
		LOG_INF("Wi-Fi TCP session finished");
#endif
	}
}

int config_pta(bool is_ant_mode_sep, bool is_ot_client, bool is_wifi_server,
	bool is_sr_protocol_ble)
{
	int ret = 0;
	enum nrf_wifi_pta_wlan_op_band wlan_band = wifi_mgmt_to_pta_band(wifi_if_status.band);

	if (wlan_band == NRF_WIFI_PTA_WLAN_OP_BAND_NONE) {
		LOG_ERR("Invalid Wi-Fi band: %d", wlan_band);
		return -1;
	}

	/* Configure PTA registers of Coexistence Hardware */
	LOG_INF("Configuring PTA for %s", wifi_band_txt(wifi_if_status.band));
	ret = nrf_wifi_coex_config_pta(wlan_band, is_ant_mode_sep, is_sr_protocol_ble);
	if (ret != 0) {
		LOG_ERR("Failed to configure PTA coex hardware: %d", ret);
		return -1;
	}
	return 0;
}


void ot_throughput_test_exit(void)
{
	/** This is called if role is client. Disconnection in the
	 *case of server is taken care by the peer client
	 */
	ot_tput_test_exit();
}

void print_common_test_params(bool is_ant_mode_sep, bool test_thread, bool test_wifi,
	bool is_ot_client)
{
	bool ot_coex_enable = IS_ENABLED(CONFIG_MPSL_CX);

	LOG_INF("-------------------------------- Test parameters");

	if (test_wifi && test_thread) {
		LOG_INF("Running Wi-Fi and Thread tests");
	} else {
		if (test_wifi) {
			LOG_INF("Running Wi-Fi only test");
		} else {
			LOG_INF("Running Thread only test");
		}
	}
	LOG_INF("Test duration in milliseconds: %d", CONFIG_COEX_TEST_DURATION);
	if (is_ant_mode_sep) {
		LOG_INF("Antenna mode : Separate antennas");
	} else {
		LOG_INF("Antenna mode : Shared antennas");
	}
	if (is_ot_client) {
		LOG_INF("Thread device role : Client");
	} else {
		LOG_INF("Thread device role : Server");
	}
	if (ot_coex_enable) {
		LOG_INF("Thread device posts requests to PTA");
	} else {
		LOG_INF("Thread device doesn't post requests to PTA");
	}
	LOG_INF("--------------------------------");
}

int print_wifi_tput_ot_tput_test_details(bool is_ot_client, bool is_wifi_server,
	bool is_wifi_zperf_udp, bool is_ot_zperf_udp)
{
	if (is_wifi_zperf_udp && (!is_wifi_server) && is_ot_zperf_udp && is_ot_client) {
		LOG_INF(" Test case:  Wi-Fi UDP client Thread UDP client");
	} else if (is_wifi_zperf_udp && (!is_wifi_server) && is_ot_zperf_udp &&
		(!is_ot_client)) {
		LOG_INF(" Test case:  Wi-Fi UDP client Thread UDP server");
	} else if (is_wifi_zperf_udp && (!is_wifi_server) && (!is_ot_zperf_udp) &&
		is_ot_client) {
		LOG_INF(" Test case:  Wi-Fi UDP client Thread TCP client");
	} else if (is_wifi_zperf_udp && (!is_wifi_server) && (!is_ot_zperf_udp) &&
		(!is_ot_client)) {
		LOG_INF(" Test case:  Wi-Fi UDP client Thread TCP server");
	} else if ((!is_wifi_zperf_udp) && (!is_wifi_server) && is_ot_zperf_udp &&
		is_ot_client) {
		LOG_INF(" Test case:  Wi-Fi TCP client Thread UDP client");
	} else if ((!is_wifi_zperf_udp) && (!is_wifi_server) && is_ot_zperf_udp &&
		(!is_ot_client)) {
		LOG_INF(" Test case:  Wi-Fi TCP client Thread UDP server");
	} else if ((!is_wifi_zperf_udp) && (!is_wifi_server) && (!is_ot_zperf_udp) &&
		is_ot_client) {
		LOG_INF(" Test case:  Wi-Fi TCP client Thread TCP client");
	} else if ((!is_wifi_zperf_udp) && (!is_wifi_server) && (!is_ot_zperf_udp) &&
		(!is_ot_client)) {
		LOG_INF(" Test case:  Wi-Fi TCP client Thread TCP server");
	} else if (is_wifi_zperf_udp && (is_wifi_server) && is_ot_zperf_udp &&
		is_ot_client) {
		LOG_INF(" Test case:  Wi-Fi UDP server Thread UDP client");
	} else if (is_wifi_zperf_udp && (is_wifi_server) && is_ot_zperf_udp &&
		(!is_ot_client)) {
		LOG_INF(" Test case:  Wi-Fi UDP server Thread UDP server");
	} else if (is_wifi_zperf_udp && (is_wifi_server) && (!is_ot_zperf_udp) &&
		is_ot_client) {
		LOG_INF(" Test case:  Wi-Fi UDP server Thread TCP client");
	} else if (is_wifi_zperf_udp && (is_wifi_server) && (!is_ot_zperf_udp) &&
		(!is_ot_client)) {
		LOG_INF(" Test case:  Wi-Fi UDP server Thread TCP server");
	} else if ((!is_wifi_zperf_udp) && (is_wifi_server) && is_ot_zperf_udp &&
		is_ot_client) {
		LOG_INF(" Test case:  Wi-Fi TCP server Thread UDP client");
	} else if ((!is_wifi_zperf_udp) && (is_wifi_server) && is_ot_zperf_udp &&
		(!is_ot_client)) {
		LOG_INF(" Test case:  Wi-Fi TCP server Thread UDP server");
	} else if ((!is_wifi_zperf_udp) && (is_wifi_server) && (!is_ot_zperf_udp)
			&& is_ot_client) {
		LOG_INF(" Test case:  Wi-Fi TCP server Thread TCP client");
	} else if ((!is_wifi_zperf_udp) && (is_wifi_server) && (!is_ot_zperf_udp) &&
		(!is_ot_client)) {
		LOG_INF(" Test case:  Wi-Fi TCP server Thread TCP server");
	} else {
		LOG_INF(" Test case:wifi_tput_ot_tput WRONG Wi-Fi and OT UDP/TCP option");
		return -1;
	}
	return 0;
}




int wifi_tput_ot_tput(bool test_wifi, bool is_ant_mode_sep, bool test_thread, bool is_ot_client,
	bool is_wifi_server, bool is_wifi_zperf_udp, bool is_ot_zperf_udp, bool is_sr_protocol_ble)
{
	int ret = 0;
	uint64_t test_start_time = 0;

	LOG_INF(" Test case:wifi_tput_ot_tput");

	ret = print_wifi_tput_ot_tput_test_details(is_ot_client, is_wifi_server,
			is_wifi_zperf_udp,	is_ot_zperf_udp);
	if (ret != 0) {
		return ret;
	}
	print_common_test_params(is_ant_mode_sep, test_thread, test_wifi, is_ot_client);

	if (is_ot_client) {
		is_ot_device_role_client = true;
	} else {
		is_ot_device_role_client = false;
	}

	if (test_wifi) {
		ret = wifi_connection();
		k_sleep(K_SECONDS(3));
		if (ret != 0) {
			LOG_ERR("Wi-Fi connection failed. Running the test");
			LOG_ERR("further is not meaningful. So, exiting the test");
			return ret;
		}
#if defined(CONFIG_NRF70_SR_COEX)
		config_pta(is_ant_mode_sep, is_ot_client, is_wifi_server, is_sr_protocol_ble);
#endif/* CONFIG_NRF70_SR_COEX */
	}
	if (test_thread) {
		LOG_INF("Thread operating channel = %d", CONFIG_OT_CHANNEL);
	}
	if (test_thread) {
		if (!is_ot_client) {
			LOG_INF("Make sure peer Thread role is client");
			k_sleep(K_SECONDS(3));
		}

		ret = ot_throughput_test_init(is_ot_client, is_ot_zperf_udp);
		k_sleep(K_SECONDS(3));
		if (ret != 0) {
			LOG_ERR("Thread throughput init failed: %d", ret);
			return ret;
		}

		if (is_ot_client) {
			/* nothing */
		} else {
			/* wait until the peer client joins the network */
			uint32_t print_wait_on_ping_reply = 1;

			while (ot_wait4_ping_reply_from_peer == 0) {
				if (print_wait_on_ping_reply) {
					LOG_INF("Waiting on ping reply from peer");
					print_wait_on_ping_reply = 0;
				}
				ot_get_peer_address(5000);
				k_sleep(K_SECONDS(1));
				if (ot_wait4_ping_reply_from_peer) {
					break;
				}
			}
		}
	}

	if (!is_wifi_server) {
#ifdef DEMARCATE_TEST_START
		LOG_INF("-------------------------start");
#endif
	}

	if (!is_wifi_server) {
		test_start_time = k_uptime_get_32();
	}

	if (test_wifi) {
		if (is_wifi_zperf_udp) {
			ret = run_wifi_traffic_udp(is_wifi_server);
		} else {
			ret = run_wifi_traffic_tcp(is_wifi_server);
		}

		if (ret != 0) {
			LOG_ERR("Failed to start Wi-Fi benchmark: %d", ret);
			return ret;
		}
		if (is_wifi_server) {
			while (!wait4_peer_wifi_client_to_start_tput) {
				k_sleep(K_SECONDS(1));
			}
			wait4_peer_wifi_client_to_start_tput = 0;
			test_start_time = k_uptime_get_32();
		}
	}

	if (test_thread) {
		if (is_ot_client) {
			/* run Thread activity and wait for the test duration */
			ot_throughput_test_run(is_ot_zperf_udp);
		} else {
			/* Peer Thread that acts as client runs the traffic. */
			while (true) {
				if ((k_uptime_get_32() - test_start_time) >
					CONFIG_COEX_TEST_DURATION) {
					break;
				}
				k_sleep(KSLEEP_WHILE_CHECK_1SEC);
				/* k_sleep(KSLEEP_100MSEC); */
			}
		}
	}

	if (is_wifi_server) {
#ifdef DEMARCATE_TEST_START
		LOG_INF("-------------------------start");
#endif
	}

	if (test_wifi) {
		check_wifi_traffic();
	}

	if (test_thread) {
		if (is_ot_client) {
			while (1) {
				k_sleep(K_MSEC(1000));
				if ((k_uptime_get_32() - test_start_time) >
					CONFIG_COEX_TEST_DURATION) {
					break;
				}
			}
		}
	}
	LOG_INF("Waiting before Wi-Fi and/or Thread disconnection");
	k_sleep(K_MSEC(3000));
	if (test_wifi) {
		wifi_disconnection();
	}

	if (test_thread) {
		/* Thread device Tx power and RSSI */
		int8_t ot_tx_power = 0;
		int8_t ot_rssi = 0;

		otInstance *ot_instance = openthread_get_default_instance();
		/* otPlatRadioSetTransmitPower(ot_instance, -3); */
		/* Get the current transmit power of OT device */
		otPlatRadioGetTransmitPower(ot_instance, &ot_tx_power);
		/* LOG_INF("OT device Tx power in dBm = %d", ot_tx_power); */

		/* The RSSI in dBm when it is valid.  127 when RSSI is invalid */
		ot_rssi = otPlatRadioGetRssi(ot_instance);
		/* LOG_INF("OT device RSSI in dBm = %d", ot_rssi); */
	}

	if (test_thread) {
		ot_throughput_test_exit();
	}

#ifdef DEMARCATE_TEST_START
	LOG_INF("-------------------------end");
#endif

	return 0;
}
```

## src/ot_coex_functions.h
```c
/*
 * Copyright (c) 2024 Nordic Semiconductor ASA
 *
 * SPDX-License-Identifier: LicenseRef-Nordic-5-Clause
 */

#ifndef OT_COEX_FUNCTIONS_
#define OT_COEX_FUNCTIONS_

#include <stdio.h>
#include <stdlib.h>
#include <string.h>

#include <zephyr/logging/log.h>
LOG_MODULE_REGISTER(ot_coex_functions, CONFIG_LOG_DEFAULT_LEVEL);

#include <zephyr/kernel.h>
#include <zephyr/init.h>
#include <zephyr/device.h>
#include <zephyr/devicetree.h>
#include <zephyr/drivers/gpio.h>
#include <zephyr/shell/shell.h>
#include <zephyr/shell/shell_uart.h>
#include <zephyr/sys/byteorder.h>
#include <zephyr/net/zperf.h>
#include <zephyr/net/net_if.h>
#include <zephyr/net/wifi_mgmt.h>
#include <zephyr/net/net_event.h>
#include <zephyr/net/socket.h>
#include <zephyr/net/wifi_utils.h>


/* For net_sprint_ll_addr_buf */
#include "net_private.h"

#include "coex.h"
#include "coex_struct.h"
#include "ot_utils.h"

#define DEMARCATE_TEST_START

#define KSLEEP_WHILE_CHECK_1SEC K_SECONDS(1)
#define KSLEEP_100MSEC K_MSEC(100)

static uint8_t wait4_peer_wifi_client_to_start_tput;

static struct sockaddr_in in4_addr_my = {
	.sin_family = AF_INET,
	.sin_port = htons(CONFIG_NET_CONFIG_PEER_IPV4_PORT),
};

static struct {
	uint8_t connected :1;
	uint8_t disconnect_requested: 1;
	uint8_t _unused : 6;
} wifi_context;

K_SEM_DEFINE(wait_for_next, 0, 1);
K_SEM_DEFINE(udp_tcp_callback, 0, 1);

/**
 * @brief configure PTA registers
 *
 * @return Zero on success or (negative) error code otherwise.
 */
int config_pta(bool is_ant_mode_sep, bool is_ot_client,
				bool is_wifi_server, bool is_sr_protocol_ble);

/**
 * @brief Start wi-fi traffic for zperf udp upload or download
 *
 * @return Zero on success or (negative) error code otherwise.
 */
int run_wifi_traffic_udp(bool is_wifi_server);

/**
 * @brief Start wi-fi traffic for zperf tcp upload or download
 *
 * @return Zero on success or (negative) error code otherwise.
 */
int run_wifi_traffic_tcp(bool is_wifi_server);

/**
 * @brief check if Wi-Fi traffic is complete
 *
 * @return None
 */
void check_wifi_traffic(void);

/**
 * @brief Disconnect Wi-Fi
 *
 * @return None
 */
void wifi_disconnection(void);

/**
 * @brief Exit Thread throughput test
 *
 * @return None
 */
void ot_throughput_test_exit(void);

/**
 * @brief Print Wi-Fi status
 *
 * @return Zero on success or (negative) error code otherwise.
 */
int cmd_wifi_status(void);

/**
 * @brief Request Wi-Fi connection
 *
 * @return Zero on success or (negative) error code otherwise.
 */
int wifi_connect(void);

/**
 * @brief Request Wi-Fi disconnection
 *
 * @return Zero on success or (negative) error code otherwise.
 */
int wifi_disconnect(void);

/**
 * @brief parse Wi-Fi IPv4 address
 *
 * @return Zero on success or (negative) error code otherwise.
 */
int parse_ipv4_addr(char *host, struct sockaddr_in *addr);

/**
 * @brief wait for next Wi-Fi event
 *
 * @return Zero on success or (negative) error code otherwise.
 */
int wifi_wait_for_next_event(const char *event_name, int timeout);

/**
 * @brief Callback for UDP download results
 *
 * @return None
 */
void udp_download_results_cb(enum zperf_status status,
	struct zperf_results *result,
	void *user_data);

/**
 * @brief Callback for UDP upload results
 *
 * @return None
 */
void udp_upload_results_cb(enum zperf_status status,
	struct zperf_results *result,
	void *user_data);

/**
 * @brief Callback for TCP download results
 *
 * @return None
 */
void tcp_download_results_cb(enum zperf_status status,
	struct zperf_results *result,
	void *user_data);

/**
 * @brief Callback for TCP upload results
 *
 * @return None
 */
void tcp_upload_results_cb(enum zperf_status status,
	struct zperf_results *result,
	void *user_data);
/**
 * @brief Print common test parameters info
 *
 * @return None
 */
void print_common_test_params(bool is_ant_mode_sep, bool test_thread, bool test_wifi,
	bool is_ot_client);

/**
 * @brief Print throughput test parameters info
 *
 * @return None
 */
int print_wifi_tput_ot_tput_test_details(bool is_ot_client, bool is_wifi_server,
	bool is_wifi_zperf_udp,	bool is_ot_zperf_udp);

/* wifi_utils.h */
#define MAX_SSID_LEN 32
#define WIFI_CONNECTION_TIMEOUT_SEC 30 /* in seconds */
#define WIFI_DHCP_TIMEOUT_SEC 10 /* in seconds */

#define DEMARCATE_TEST_START

#define TXPOWER_INIT_VALUE 127
#define RSSI_INIT_VALUE 127

#define HIGHEST_CHANNUM_24G 14

uint32_t wifi_disconn_success_cnt;
uint32_t wifi_disconn_fail_cnt;
uint32_t wifi_disconn_no_conn_cnt;

int8_t wifi_rssi = RSSI_INIT_VALUE;
static int print_wifi_conn_status_once = 1;

struct wifi_iface_status wifi_if_status = { 0 };

static struct net_mgmt_event_callback wifi_sta_mgmt_cb;
static struct net_mgmt_event_callback net_addr_mgmt_cb;

#define WIFI_MGMT_EVENTS (NET_EVENT_WIFI_CONNECT_RESULT | NET_EVENT_WIFI_DISCONNECT_RESULT)

/**
 * @brief Handle Wi-Fi management events
 *
 * @return No return value.
 */
void wifi_mgmt_event_handler(struct net_mgmt_event_callback *cb, uint64_t mgmt_event,
	struct net_if *iface);

/**
 * @brief Handle net management events
 *
 * @return No return value.
 */
void net_mgmt_event_handler(struct net_mgmt_event_callback *cb, uint64_t mgmt_event,
	struct net_if *iface);

/**
 * @brief Callback for Wi-Fi connection result
 *
 * @return No return value.
 */
void handle_wifi_connect_result(struct net_mgmt_event_callback *cb);

/**
 * @brief Callback for Wi-Fi disconnection result
 *
 * @return No return value.
 */
void handle_wifi_disconnect_result(struct net_mgmt_event_callback *cb);

/**
 * @brief Callback for Wi-Fi scan result
 *
 * @return No return value.
 */
void handle_wifi_scan_result(struct net_mgmt_event_callback *cb);

/**
 * @brief Callback for Wi-Fi scan done
 *
 * @return No return value.
 */
void handle_wifi_scan_done(struct net_mgmt_event_callback *cb);

/**
 * @brief Callback for Wi-Fi DHCP IP address
 *
 * @return None
 */
void print_dhcp_ip(struct net_mgmt_event_callback *cb);

#endif /* OT_COEX_FUNCTIONS_ */
```

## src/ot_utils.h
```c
/*
 * Copyright (c) 2024 Nordic Semiconductor ASA
 *
 * SPDX-License-Identifier: LicenseRef-Nordic-5-Clause
 */

#ifndef OT_UTILS_H_
#define OT_UTILS_H_

#include <stdint.h>
#include <stdbool.h>
#include <string.h>
#include <stdlib.h>
#include <assert.h>
#include <inttypes.h>

#include "zephyr/net/openthread.h"

#include <openthread/instance.h>
#include <zephyr/version.h>
#include <openthread/config.h>
#include <openthread/cli.h>
#include <openthread/diag.h>
#include <openthread/error.h>
#include <openthread/joiner.h>
#include <openthread/link.h>
#include <openthread/tasklet.h>
#include <openthread/platform/logging.h>
#include <openthread/dataset_ftd.h>
#include <openthread/thread.h>

#include <openthread/platform/radio.h>

/**
 * Initialize Thread throughput test
 *
 * @return Zero on success or (negative) error code otherwise.
 */
int ot_throughput_test_init(bool is_ot_client, bool is_ot_zperf_udp);

/**
 * @brief Run Thread throughput test
 *
 * @return Zero on success or (negative) error code otherwise.
 */
int ot_throughput_test_run(bool is_ot_zperf_udp);

/**
 * @brief Exit Thread throughput test
 *
 * @return Zero on success or (negative) error code otherwise.
 */
int ot_tput_test_exit(void);

/**
 * Initialize Thread device
 *
 * @return Zero on success or (negative) error code otherwise.
 */
int ot_initialization(void);

/**
 * @brief Start thread joiner
 *
 * @return None.
 */
void ot_start_joiner(const char *pskd);

/**
 * @brief Set thread network key to null
 *
 * @return None.
 */
void ot_setNullNetworkKey(otInstance *aInstance);

/**
 * @brief Get peer address
 *
 * @return None.
 */
void ot_get_peer_address(uint64_t timeout_ms);

/**
 * @brief Thread throughput upload
 *
 * @return None.
 */
void ot_start_zperf_test_send(const char *peer_addr, uint32_t duration_sec,
		uint32_t packet_size_bytes, uint32_t rate_bps, bool is_ot_zperf_udp);

/**
 * @brief Thread throughput download
 *
 * @return None.
 */
void ot_start_zperf_test_recv(bool is_ot_zperf_udp);

/**
 * @brief Thread throughput test
 *
 * @return None.
 */
void ot_zperf_test(bool is_ot_zperf_udp);

/**
 * @brief Configure Thread network
 *
 * @return None.
 */
void ot_setNetworkConfiguration(otInstance *aInstance);

#endif /* OT_UTILS_H_ */
```

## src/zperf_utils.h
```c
/*
 * Copyright (c) 2024 Nordic Semiconductor ASA
 *
 * SPDX-License-Identifier: LicenseRef-Nordic-5-Clause
 */

#include <ctype.h>
#include <stdio.h>
#include <stdlib.h>
#include <strings.h>

#include <zephyr/kernel.h>
#include <zephyr/net/net_ip.h>
#include <zephyr/net/net_core.h>
#include <zephyr/net/socket.h>
#include <zephyr/net/zperf.h>

/**
 * @brief thread zperf upload
 *
 * @return Zero on success or (negative) error code otherwise.
 */
int zperf_upload(const char *peer_addr, uint32_t duration_sec, uint32_t packet_size_bytes,
	uint32_t rate_bps, bool is_ot_zperf_udp);

/**
 * @brief thread zperf upload statistics
 *
 * @return None
 */
void zperf_log_upload_stats(struct zperf_results *results, bool is_udp);

/**
 * @brief thread zperf download
 *
 * @return Zero on success or (negative) error code otherwise.
 */
int zperf_download(bool is_udp);

/**
 * @brief thread zperf download callback
 *
 * @return None
 */
void zperf_download_cb(enum zperf_status status,
	struct zperf_results *result,
	void *user_data);
```
